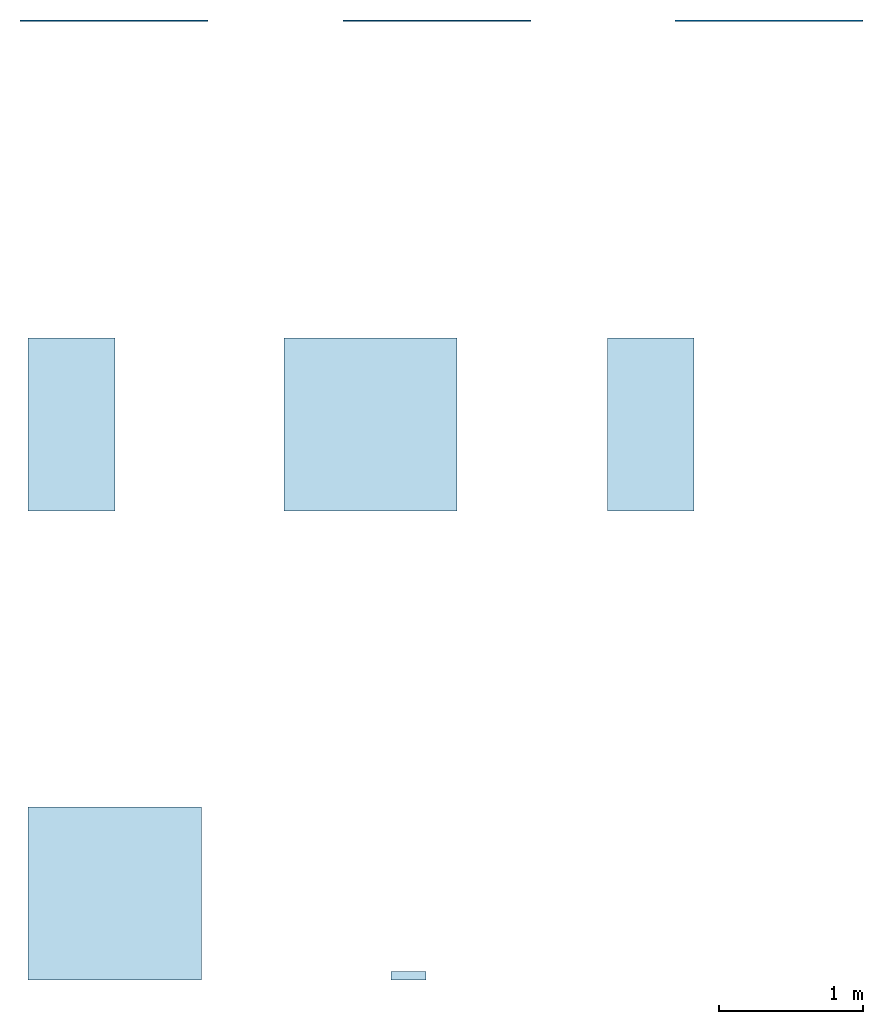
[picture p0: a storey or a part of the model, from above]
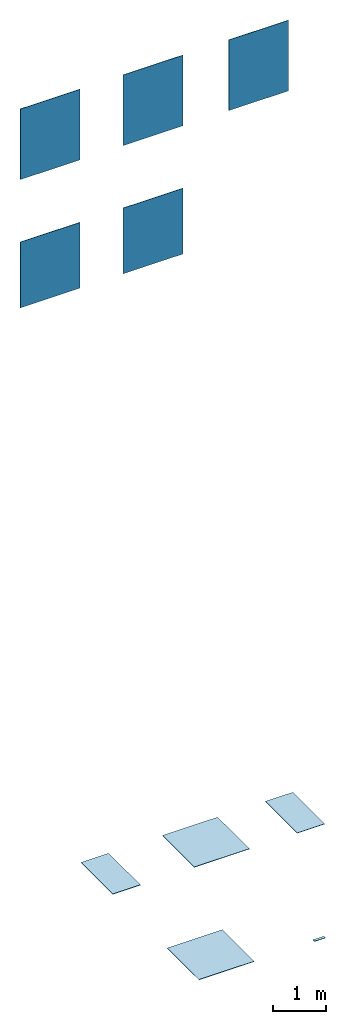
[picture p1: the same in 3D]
Properties of the parts of a building model (IFC2X3)

# File
Description: ViewDefinition [CoordinationView_V2.0], RevitIdentifiers [VersionGUID: 82abf02f-c951-44b0-89b2-05196ea78783, NumberOfSaves: 553], CoordinateReference [CoordinateBase: Shared Coordinates, ProjectSite: Internal]
File name: Project Number
Time: 2023-12-11T16:26:15+01:00
Written by: ODA SDAI 24.3
Made in: Autodesk Revit 24.1.11.26 (ENU) - IFC 24.1.11.26

# IfcProject, Project Number
LongName: Refin-Blended; Phase: Project Status

# IfcSite, Default
RefLatitude: 51, 30, 0, 549316; RefLongitude: 0, -7, -34, -450321; RefElevation: 0 mm

# IfcBuilding
Pset_BuildingCommon - NumberOfStoreys: 1

# IfcBuildingStorey: Level:Circle Head - Project Datum (2)
Pset_AirSideSystemInformation - sets with these values: 2
Name | LongName = Name | Elevation (mm)
Level 0 | Level 0 | 0
Level 1 | Level 1 | 4000

# IfcSlab: Floor:Floor_Tiles_Refin-Cera-Luce-Cerasilk_120x120_RA31, Floor:Floor_Tiles_Refin-Cera-Luce-Cerasilk_120x120_RA31:363144
In: Level 0
Type - PredefinedType: FLOOR; Material: Cera-Luce-Cerasilk-120x120 RA31 9 mm, <Unnamed> 1 mm
Type - Pset_ConcreteElementGeneral - FireRating: INERT
Type - Pset_ElementShading - Color: WHITE
Type - Pset_FireRatingProperties - SurfaceSpreadOfFlame: INERT
Type - Pset_ManufacturerOccurrence - BarCode: N/A; SerialNumber: N/A
Type - Pset_ManufacturerTypeInformation - ArticleNumber: RA31; ModelReference: RA31; ModelLabel: CERA LUCE CERASILK R 120X120; Manufacturer: info@refin.it; ProductionYear: N/A
Type - Pset_PrecastConcreteElementGeneral - SerialNumber: N/A
Type - Pset_ProductRequirements - Name: Cera_Luce_Cerasilk_120X120 R; Category: Pr_35_93_96_19:Ceramic tiles
Type - Pset_QuantityTakeOff - Reference: N/A
Type - Pset_ReinforcementBarPitchOfSlab - Description: PORCELAIN STONEWARE TILE; Reference: N/A
Type - Pset_SlabCommon - Reference: N/A; IsExternal: no; AcousticRating: N/A; FireRating: INERT; SurfaceSpreadOfFlame: INERT
Type - Pset_Warranty - WarrantyContent: N/A; Exclusions: N/A
Pset_QuantityTakeOff - sets with these values: 2
Pset_SlabCommon - LoadBearing: no; PitchAngle: 0 deg

# IfcSlab: Floor:Floor_Tiles_Refin-Cera-Luce-Cerasilk_60x120_RA34, Floor:Floor_Tiles_Refin-Cera-Luce-Cerasilk_60x120_RA34:340059
In: Level 0
Type - PredefinedType: FLOOR; Material: Cera-Luce-Cerasilk-60x120 RA34 9 mm, <Unnamed> 1 mm
Type - Pset_ConcreteElementGeneral - FireRating: INERT
Type - Pset_ElementShading - Color: WHITE
Type - Pset_FireRatingProperties - SurfaceSpreadOfFlame: INERT
Type - Pset_ManufacturerOccurrence - BarCode: N/A; SerialNumber: N/A
Type - Pset_ManufacturerTypeInformation - ArticleNumber: RA34; ModelReference: RA34; ModelLabel: CERA LUCE CERASILK R 60X120; Manufacturer: info@refin.it; ProductionYear: N/A
Type - Pset_PrecastConcreteElementGeneral - SerialNumber: N/A
Type - Pset_ProductRequirements - Name: Cera_Luce_Cerasilk_60X120 R; Category: Pr_35_93_96_19:Ceramic tiles
Type - Pset_QuantityTakeOff - Reference: N/A
Type - Pset_ReinforcementBarPitchOfSlab - Description: PORCELAIN STONEWARE TILE; Reference: N/A
Type - Pset_SlabCommon - Reference: N/A; IsExternal: no; AcousticRating: N/A; FireRating: INERT; SurfaceSpreadOfFlame: INERT
Type - Pset_Warranty - WarrantyContent: N/A; Exclusions: N/A
Pset_QuantityTakeOff - sets with these values: 2
Pset_SlabCommon - LoadBearing: no; PitchAngle: 0 deg

# IfcSlab: Floor:Floor_Tiles_Refin-Cera-Luce-Matt-Pro_120x120_RD53, Floor:Floor_Tiles_Refin-Cera-Luce-Matt-Pro_120x120_RD53:363964
In: Level 0
Type - PredefinedType: FLOOR; Material: Cera-Luce-Matt-Pro-120x120 RD53 9 mm, <Unnamed> 1 mm
Type - Pset_ConcreteElementGeneral - FireRating: INERT
Type - Pset_ElementShading - Color: WHITE
Type - Pset_FireRatingProperties - SurfaceSpreadOfFlame: INERT
Type - Pset_ManufacturerOccurrence - BarCode: N/A; SerialNumber: N/A
Type - Pset_ManufacturerTypeInformation - ArticleNumber: RD53; ModelReference: RD53; ModelLabel: CERA LUCE MATTO-PRO R 120X120; Manufacturer: info@refin.it; ProductionYear: N/A
Type - Pset_PrecastConcreteElementGeneral - SerialNumber: N/A
Type - Pset_ProductRequirements - Name: Cera_Luce_Matt_Pro_120X120 R; Category: Pr_35_93_96_19:Ceramic tiles
Type - Pset_QuantityTakeOff - Reference: N/A
Type - Pset_ReinforcementBarPitchOfSlab - Description: PORCELAIN STONEWARE TILE; Reference: N/A
Type - Pset_SlabCommon - Reference: N/A; IsExternal: no; AcousticRating: N/A; FireRating: INERT; SurfaceSpreadOfFlame: INERT
Type - Pset_Warranty - WarrantyContent: N/A; Exclusions: N/A
Pset_QuantityTakeOff - sets with these values: 2
Pset_SlabCommon - LoadBearing: no; PitchAngle: 0 deg

# IfcSlab: Floor:Floor_Tiles_Refin-Cera-Luce-Matt-Pro_60x120_RD56, Floor:Floor_Tiles_Refin-Cera-Luce-Matt-Pro_60x120_RD56:363584
In: Level 0
Type - PredefinedType: FLOOR; Material: Cera-Luce-Matt-Pro-60x120 RD56 9 mm, <Unnamed> 1 mm
Type - Pset_ConcreteElementGeneral - FireRating: INERT
Type - Pset_ElementShading - Color: WHITE
Type - Pset_FireRatingProperties - SurfaceSpreadOfFlame: INERT
Type - Pset_ManufacturerOccurrence - BarCode: N/A; SerialNumber: N/A
Type - Pset_ManufacturerTypeInformation - ArticleNumber: RD56; ModelReference: RD56; ModelLabel: CERA LUCE MATT-PRO R 60X120; Manufacturer: info@refin.it; ProductionYear: N/A
Type - Pset_PrecastConcreteElementGeneral - SerialNumber: N/A
Type - Pset_ProductRequirements - Name: Cera_Luce_Matt_Pro_60X120 R; Category: Pr_35_93_96_19:Ceramic tiles
Type - Pset_QuantityTakeOff - Reference: N/A
Type - Pset_ReinforcementBarPitchOfSlab - Description: PORCELAIN STONEWARE TILE; Reference: N/A
Type - Pset_SlabCommon - Reference: N/A; IsExternal: no; AcousticRating: N/A; FireRating: INERT; SurfaceSpreadOfFlame: INERT
Type - Pset_Warranty - WarrantyContent: N/A; Exclusions: N/A
Pset_QuantityTakeOff - sets with these values: 2
Pset_SlabCommon - LoadBearing: no; PitchAngle: 0 deg

# IfcSlab: Floor:Floor_Tiles_Refin-Cera-Wax-Luce_6x24_RC65, Floor:Floor_Tiles_Refin-Cera-Wax-Luce_6x24_RC65:364588
In: Level 0
Type - PredefinedType: FLOOR; Material: Cera-Wax-Luce-6x24 RC65 8.5 mm, <Unnamed> 1 mm
Type - Pset_ConcreteElementGeneral - FireRating: INERT
Type - Pset_ElementShading - Color: WHITE
Type - Pset_FireRatingProperties - SurfaceSpreadOfFlame: INERT
Type - Pset_ManufacturerOccurrence - BarCode: N/A; SerialNumber: N/A
Type - Pset_ManufacturerTypeInformation - ArticleNumber: RC65; ModelReference: RC65; ModelLabel: CERA WAX LUCE 6X24; Manufacturer: info@refin.it; ProductionYear: N/A
Type - Pset_PrecastConcreteElementGeneral - SerialNumber: N/A
Type - Pset_ProductRequirements - Name: Cera_Wax_Luce_6X24; Category: Pr_35_93_96_19:Ceramic tiles
Type - Pset_QuantityTakeOff - Reference: N/A
Type - Pset_ReinforcementBarPitchOfSlab - Description: PORCELAIN STONEWARE TILE; Reference: N/A
Type - Pset_SlabCommon - Reference: N/A; IsExternal: no; AcousticRating: N/A; FireRating: INERT; SurfaceSpreadOfFlame: INERT
Type - Pset_Warranty - WarrantyContent: N/A; Exclusions: N/A
Pset_QuantityTakeOff - sets with these values: 2
Pset_SlabCommon - LoadBearing: no; PitchAngle: 0 deg

# IfcWallStandardCase: Basic Wall:Wall_Tiles_Refin-Cera-Luce-Cerasilk_120x120_RA31, Basic Wall:Wall_Tiles_Refin-Cera-Luce-Cerasilk_120x120_RA31:363313
In: Level 0
Type - PredefinedType: STANDARD; Material: <Unnamed> 1 mm, Cera-Luce-Cerasilk-120x120 RA31 9 mm
Type - Pset_ElementShading - Color: WHITE
Type - Pset_FireRatingProperties - SurfaceSpreadOfFlame: INERT
Type - Pset_ManufacturerOccurrence - BarCode: N/A; SerialNumber: N/A
Type - Pset_ManufacturerTypeInformation - ArticleNumber: RA31; ModelReference: RA31; ModelLabel: CERA LUCE CERASILK R 120X120; Manufacturer: info@refin.it; ProductionYear: N/A
Type - Pset_PrecastConcreteElementGeneral - SerialNumber: N/A
Type - Pset_ProductRequirements - Name: Cera_Luce_Cerasilk_120X120 R; Category: Pr_35_93_96_19:Ceramic tiles
Type - Pset_QuantityTakeOff - Reference: N/A
Type - Pset_ReinforcementBarPitchOfWall - Description: PORCELAIN STONEWARE TILE; Reference: N/A
Type - Pset_WallCommon - Reference: N/A; IsExternal: no; AcousticRating: N/A; SurfaceSpreadOfFlame: INERT
Type - Pset_Warranty - WarrantyContent: N/A; Exclusions: N/A
Pset_QuantityTakeOff - sets with these values: 2
Pset_WallCommon - ExtendToStructure: no; LoadBearing: no

# IfcWallStandardCase: Basic Wall:Wall_Tiles_Refin-Cera-Luce-Cerasilk_60x120_RA34, Basic Wall:Wall_Tiles_Refin-Cera-Luce-Cerasilk_60x120_RA34:334895
In: Level 0
Type - PredefinedType: STANDARD; Material: <Unnamed> 1 mm, Cera-Luce-Cerasilk-60x120 RA34 9 mm
Type - Pset_ElementShading - Color: WHITE
Type - Pset_FireRatingProperties - SurfaceSpreadOfFlame: INERT
Type - Pset_ManufacturerOccurrence - BarCode: N/A; SerialNumber: N/A
Type - Pset_ManufacturerTypeInformation - ArticleNumber: RA34; ModelReference: RA34; ModelLabel: CERA LUCE CERASILK R 60X120; Manufacturer: info@refin.it; ProductionYear: N/A
Type - Pset_PrecastConcreteElementGeneral - SerialNumber: N/A
Type - Pset_ProductRequirements - Name: Cera_Luce_Cerasilk_60X120 R; Category: Pr_35_93_96_19:Ceramic tiles
Type - Pset_QuantityTakeOff - Reference: N/A
Type - Pset_ReinforcementBarPitchOfWall - Description: PORCELAIN STONEWARE TILE; Reference: N/A
Type - Pset_WallCommon - Reference: N/A; IsExternal: no; AcousticRating: N/A; SurfaceSpreadOfFlame: INERT
Type - Pset_Warranty - WarrantyContent: N/A; Exclusions: N/A
Pset_QuantityTakeOff - sets with these values: 2
Pset_WallCommon - ExtendToStructure: no; LoadBearing: no

# IfcWallStandardCase: Basic Wall:Wall_Tiles_Refin-Cera-Luce-Matt-Pro_120x120_RD53, Basic Wall:Wall_Tiles_Refin-Cera-Luce-Matt-Pro_120x120_RD53:364401
In: Level 0
Type - PredefinedType: STANDARD; Material: <Unnamed> 1 mm, Cera-Luce-Matt-Pro-120x120 RD53 9 mm
Type - Pset_ElementShading - Color: WHITE
Type - Pset_FireRatingProperties - SurfaceSpreadOfFlame: INERT
Type - Pset_ManufacturerOccurrence - BarCode: N/A; SerialNumber: N/A
Type - Pset_ManufacturerTypeInformation - ArticleNumber: RD53; ModelReference: RD53; ModelLabel: CERA LUCE MATT-PRO R 120X120; Manufacturer: info@refin.it; ProductionYear: N/A
Type - Pset_PrecastConcreteElementGeneral - SerialNumber: N/A
Type - Pset_ProductRequirements - Name: Cera_Luce_Matt_Pro_120X120 R; Category: Pr_35_93_96_19:Ceramic tiles
Type - Pset_QuantityTakeOff - Reference: N/A
Type - Pset_ReinforcementBarPitchOfWall - Description: PORCELAIN STONEWARE TILE; Reference: N/A
Type - Pset_WallCommon - Reference: N/A; IsExternal: no; AcousticRating: N/A; SurfaceSpreadOfFlame: INERT
Type - Pset_Warranty - WarrantyContent: N/A; Exclusions: N/A
Pset_QuantityTakeOff - sets with these values: 2
Pset_WallCommon - ExtendToStructure: no; LoadBearing: no

# IfcWallStandardCase: Basic Wall:Wall_Tiles_Refin-Cera-Luce-Matt-Pro_60x120_RD56, Basic Wall:Wall_Tiles_Refin-Cera-Luce-Matt-Pro_60x120_RD56:363798
In: Level 0
Type - PredefinedType: STANDARD; Material: <Unnamed> 1 mm, Cera-Luce-Matt-Pro-60x120 RD56 9 mm
Type - Pset_ElementShading - Color: WHITE
Type - Pset_FireRatingProperties - SurfaceSpreadOfFlame: INERT
Type - Pset_ManufacturerOccurrence - BarCode: N/A; SerialNumber: N/A
Type - Pset_ManufacturerTypeInformation - ArticleNumber: RD56; ModelReference: RD56; ModelLabel: CERA LUCE MATT-PRO R 60X120; Manufacturer: info@refin.it; ProductionYear: N/A
Type - Pset_PrecastConcreteElementGeneral - SerialNumber: N/A
Type - Pset_ProductRequirements - Name: Cera_Luce_Matt_Pro_60X120 R; Category: Pr_35_93_96_19:Ceramic tiles
Type - Pset_QuantityTakeOff - Reference: N/A
Type - Pset_ReinforcementBarPitchOfWall - Description: PORCELAIN STONEWARE TILE; Reference: N/A
Type - Pset_WallCommon - Reference: N/A; IsExternal: no; AcousticRating: N/A; SurfaceSpreadOfFlame: INERT
Type - Pset_Warranty - WarrantyContent: N/A; Exclusions: N/A
Pset_QuantityTakeOff - sets with these values: 2
Pset_WallCommon - ExtendToStructure: no; LoadBearing: no

# IfcWallStandardCase: Basic Wall:Wall_Tiles_Refin-Cera-Wax-Luce_6x24_RC65, Basic Wall:Wall_Tiles_Refin-Cera-Wax-Luce_6x24_RC65:365073
In: Level 0
Type - PredefinedType: STANDARD; Material: <Unnamed> 1 mm, Cera-Wax-Luce-6x24 RC65 8.5 mm
Type - Pset_ElementShading - Color: WHITE
Type - Pset_FireRatingProperties - SurfaceSpreadOfFlame: INERT
Type - Pset_ManufacturerOccurrence - BarCode: N/A; SerialNumber: N/A
Type - Pset_ManufacturerTypeInformation - ArticleNumber: RC65; ModelReference: RC65; ModelLabel: CERA WAX LUCE 6X24; Manufacturer: info@refin.it; ProductionYear: N/A
Type - Pset_PrecastConcreteElementGeneral - SerialNumber: N/A
Type - Pset_ProductRequirements - Name: Cera_Wax_Luce_6X24; Category: Pr_35_93_96_19:Ceramic tiles
Type - Pset_QuantityTakeOff - Reference: N/A
Type - Pset_ReinforcementBarPitchOfWall - Description: PORCELAIN STONEWARE TILE; Reference: N/A
Type - Pset_WallCommon - Reference: N/A; IsExternal: no; AcousticRating: N/A; SurfaceSpreadOfFlame: INERT
Type - Pset_Warranty - WarrantyContent: N/A; Exclusions: N/A
Pset_QuantityTakeOff - sets with these values: 2
Pset_WallCommon - ExtendToStructure: no; LoadBearing: no
